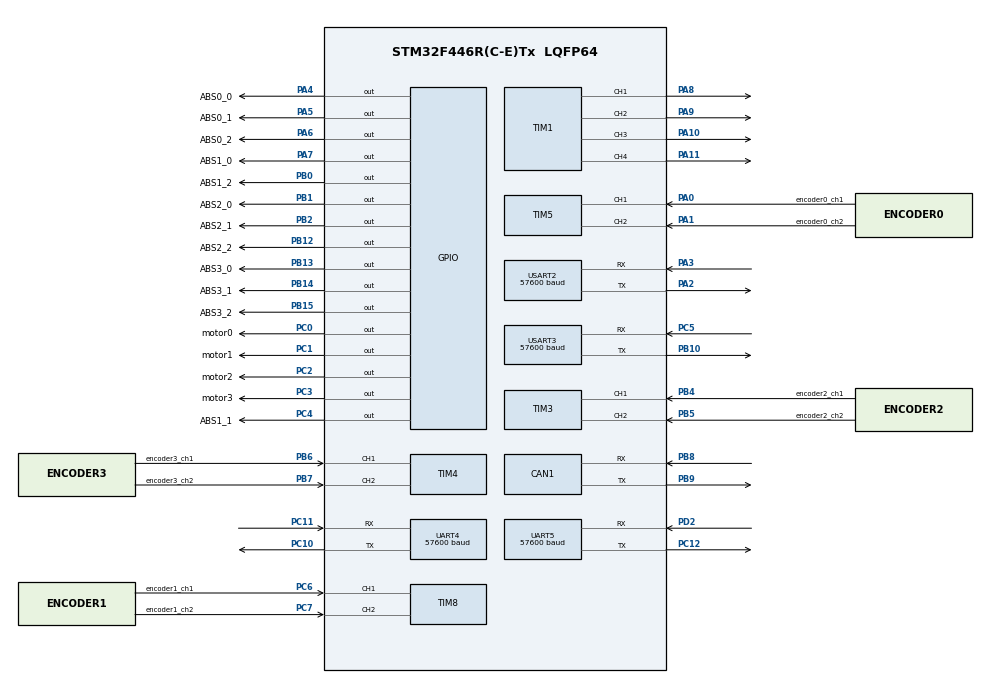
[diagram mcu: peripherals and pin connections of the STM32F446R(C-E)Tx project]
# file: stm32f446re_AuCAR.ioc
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CAN1.CalculateTimeQuantum=500.0
Dma.Request0=USART2_RX
Dma.Request1=USART2_TX
Dma.Request2=USART3_RX
Dma.Request3=USART3_TX
Dma.Request4=UART4_RX
Dma.Request5=UART4_TX
Dma.Request6=UART5_RX
Dma.Request7=UART5_TX
Dma.UART4_RX.4.Direction=DMA_PERIPH_TO_MEMORY
Dma.UART4_RX.4.FIFOMode=DMA_FIFOMODE_DISABLE
Dma.UART4_RX.4.Instance=DMA1_Stream2
Dma.UART4_RX.4.MemDataAlignment=DMA_MDATAALIGN_BYTE
Dma.UART4_RX.4.MemInc=DMA_MINC_ENABLE
Dma.UART4_RX.4.Mode=DMA_CIRCULAR
Dma.UART4_RX.4.PeriphDataAlignment=DMA_PDATAALIGN_BYTE
Dma.UART4_RX.4.PeriphInc=DMA_PINC_DISABLE
Dma.UART4_RX.4.Priority=DMA_PRIORITY_LOW
Dma.UART4_TX.5.Direction=DMA_MEMORY_TO_PERIPH
Dma.UART4_TX.5.FIFOMode=DMA_FIFOMODE_DISABLE
Dma.UART4_TX.5.Instance=DMA1_Stream4
Dma.UART4_TX.5.MemDataAlignment=DMA_MDATAALIGN_BYTE
Dma.UART4_TX.5.MemInc=DMA_MINC_ENABLE
Dma.UART4_TX.5.Mode=DMA_NORMAL
Dma.UART4_TX.5.PeriphDataAlignment=DMA_PDATAALIGN_BYTE
Dma.UART4_TX.5.PeriphInc=DMA_PINC_DISABLE
Dma.UART4_TX.5.Priority=DMA_PRIORITY_LOW
Dma.UART5_RX.6.Direction=DMA_PERIPH_TO_MEMORY
Dma.UART5_RX.6.FIFOMode=DMA_FIFOMODE_DISABLE
Dma.UART5_RX.6.Instance=DMA1_Stream0
Dma.UART5_RX.6.MemDataAlignment=DMA_MDATAALIGN_BYTE
Dma.UART5_RX.6.MemInc=DMA_MINC_ENABLE
Dma.UART5_RX.6.Mode=DMA_CIRCULAR
Dma.UART5_RX.6.PeriphDataAlignment=DMA_PDATAALIGN_BYTE
Dma.UART5_RX.6.PeriphInc=DMA_PINC_DISABLE
Dma.UART5_RX.6.Priority=DMA_PRIORITY_LOW
Dma.UART5_TX.7.Direction=DMA_MEMORY_TO_PERIPH
Dma.UART5_TX.7.FIFOMode=DMA_FIFOMODE_DISABLE
Dma.UART5_TX.7.Instance=DMA1_Stream7
Dma.UART5_TX.7.MemDataAlignment=DMA_MDATAALIGN_BYTE
Dma.UART5_TX.7.MemInc=DMA_MINC_ENABLE
Dma.UART5_TX.7.Mode=DMA_NORMAL
Dma.UART5_TX.7.PeriphDataAlignment=DMA_PDATAALIGN_BYTE
Dma.UART5_TX.7.PeriphInc=DMA_PINC_DISABLE
Dma.UART5_TX.7.Priority=DMA_PRIORITY_LOW
Dma.USART2_RX.0.Direction=DMA_PERIPH_TO_MEMORY
Dma.USART2_RX.0.FIFOMode=DMA_FIFOMODE_DISABLE
Dma.USART2_RX.0.Instance=DMA1_Stream5
Dma.USART2_RX.0.MemDataAlignment=DMA_MDATAALIGN_BYTE
Dma.USART2_RX.0.MemInc=DMA_MINC_ENABLE
Dma.USART2_RX.0.Mode=DMA_CIRCULAR
Dma.USART2_RX.0.PeriphDataAlignment=DMA_PDATAALIGN_BYTE
Dma.USART2_RX.0.PeriphInc=DMA_PINC_DISABLE
Dma.USART2_RX.0.Priority=DMA_PRIORITY_LOW
Dma.USART2_TX.1.Direction=DMA_MEMORY_TO_PERIPH
Dma.USART2_TX.1.FIFOMode=DMA_FIFOMODE_DISABLE
Dma.USART2_TX.1.Instance=DMA1_Stream6
Dma.USART2_TX.1.MemDataAlignment=DMA_MDATAALIGN_BYTE
Dma.USART2_TX.1.MemInc=DMA_MINC_ENABLE
Dma.USART2_TX.1.Mode=DMA_NORMAL
Dma.USART2_TX.1.PeriphDataAlignment=DMA_PDATAALIGN_BYTE
Dma.USART2_TX.1.PeriphInc=DMA_PINC_DISABLE
Dma.USART2_TX.1.Priority=DMA_PRIORITY_LOW
Dma.USART3_RX.2.Direction=DMA_PERIPH_TO_MEMORY
Dma.USART3_RX.2.FIFOMode=DMA_FIFOMODE_DISABLE
Dma.USART3_RX.2.Instance=DMA1_Stream1
Dma.USART3_RX.2.MemDataAlignment=DMA_MDATAALIGN_BYTE
Dma.USART3_RX.2.MemInc=DMA_MINC_ENABLE
Dma.USART3_RX.2.Mode=DMA_CIRCULAR
Dma.USART3_RX.2.PeriphDataAlignment=DMA_PDATAALIGN_BYTE
Dma.USART3_RX.2.PeriphInc=DMA_PINC_DISABLE
Dma.USART3_RX.2.Priority=DMA_PRIORITY_LOW
Dma.USART3_TX.3.Direction=DMA_MEMORY_TO_PERIPH
Dma.USART3_TX.3.FIFOMode=DMA_FIFOMODE_DISABLE
Dma.USART3_TX.3.Instance=DMA1_Stream3
Dma.USART3_TX.3.MemDataAlignment=DMA_MDATAALIGN_BYTE
Dma.USART3_TX.3.MemInc=DMA_MINC_ENABLE
Dma.USART3_TX.3.Mode=DMA_NORMAL
Dma.USART3_TX.3.PeriphDataAlignment=DMA_PDATAALIGN_BYTE
Dma.USART3_TX.3.PeriphInc=DMA_PINC_DISABLE
Dma.USART3_TX.3.Priority=DMA_PRIORITY_LOW
Mcu.Family=STM32F4
Mcu.Name=STM32F446R(C-E)Tx
Mcu.Package=LQFP64
NVIC.CAN1_RX0_IRQn=true\:0\:0\:false\:false\:true\:true\:true
NVIC.CAN1_RX1_IRQn=true\:0\:0\:false\:false\:true\:true\:true
NVIC.CAN1_SCE_IRQn=true\:0\:0\:false\:false\:true\:true\:true
NVIC.CAN1_TX_IRQn=true\:0\:0\:false\:false\:true\:true\:true
NVIC.DMA1_Stream0_IRQn=true\:0\:0\:false\:false\:true\:false\:true
NVIC.DMA1_Stream1_IRQn=true\:0\:0\:false\:false\:true\:false\:true
NVIC.DMA1_Stream2_IRQn=true\:0\:0\:false\:false\:true\:false\:true
NVIC.DMA1_Stream3_IRQn=true\:0\:0\:false\:false\:true\:false\:true
NVIC.DMA1_Stream4_IRQn=true\:0\:0\:false\:false\:true\:false\:true
NVIC.DMA1_Stream5_IRQn=true\:0\:0\:false\:false\:true\:false\:true
NVIC.DMA1_Stream6_IRQn=true\:0\:0\:false\:false\:true\:false\:true
NVIC.DMA1_Stream7_IRQn=true\:0\:0\:false\:false\:true\:false\:true
NVIC.PriorityGroup=NVIC_PRIORITYGROUP_4
NVIC.RCC_IRQn=true\:0\:0\:false\:false\:true\:true\:false
NVIC.TIM3_IRQn=true\:0\:0\:false\:false\:true\:true\:true
NVIC.TIM4_IRQn=true\:0\:0\:false\:false\:true\:true\:true
NVIC.UART4_IRQn=true\:0\:0\:false\:false\:true\:true\:true
NVIC.UART5_IRQn=true\:0\:0\:false\:false\:true\:true\:true
NVIC.USART2_IRQn=true\:0\:0\:false\:false\:true\:true\:true
NVIC.USART3_IRQn=true\:0\:0\:false\:false\:true\:true\:true
PA0-WKUP.GPIO_Label=encoder0_ch1
PA0-WKUP.Signal=S_TIM5_CH1
PA1.GPIO_Label=encoder0_ch2
PA1.Signal=S_TIM5_CH2
PA10.Signal=S_TIM1_CH3
PA11.Signal=S_TIM1_CH4
PA13.Mode=Serial_Wire
PA13.Signal=SYS_JTMS-SWDIO
PA14.Mode=Serial_Wire
PA14.Signal=SYS_JTCK-SWCLK
PA2.Mode=Asynchronous
PA2.Signal=USART2_TX
PA3.Mode=Asynchronous
PA3.Signal=USART2_RX
PA4.GPIO_Label=ABS0_0
PA4.Signal=GPIO_Output
PA5.GPIO_Label=ABS0_1
PA5.Signal=GPIO_Output
PA6.GPIO_Label=ABS0_2
PA6.Signal=GPIO_Output
PA7.GPIO_Label=ABS1_0
PA7.Signal=GPIO_Output
PA8.Signal=S_TIM1_CH1
PA9.Signal=S_TIM1_CH2
PB0.GPIO_Label=ABS1_2
PB0.Signal=GPIO_Output
PB1.GPIO_Label=ABS2_0
PB1.Signal=GPIO_Output
PB10.Mode=Asynchronous
PB10.Signal=USART3_TX
PB12.GPIO_Label=ABS2_2
PB12.Signal=GPIO_Output
PB13.GPIO_Label=ABS3_0
PB13.Signal=GPIO_Output
PB14.GPIO_Label=ABS3_1
PB14.Signal=GPIO_Output
PB15.GPIO_Label=ABS3_2
PB15.Signal=GPIO_Output
PB2.GPIO_Label=ABS2_1
PB2.Signal=GPIO_Output
PB4.GPIO_Label=encoder2_ch1
PB4.Signal=S_TIM3_CH1
PB5.GPIO_Label=encoder2_ch2
PB5.Signal=S_TIM3_CH2
PB6.GPIO_Label=encoder3_ch1
PB6.Signal=S_TIM4_CH1
PB7.GPIO_Label=encoder3_ch2
PB7.Signal=S_TIM4_CH2
PB8.Mode=Master
PB8.Signal=CAN1_RX
PB9.Mode=Master
PB9.Signal=CAN1_TX
PC0.GPIO_Label=motor0
PC0.Signal=GPIO_Output
PC1.GPIO_Label=motor1
PC1.Signal=GPIO_Output
PC10.Mode=Asynchronous
PC10.Signal=UART4_TX
PC11.Mode=Asynchronous
PC11.Signal=UART4_RX
PC12.Mode=Asynchronous
PC12.Signal=UART5_TX
PC2.GPIO_Label=motor2
PC2.Signal=GPIO_Output
PC3.GPIO_Label=motor3
PC3.Signal=GPIO_Output
PC4.GPIO_Label=ABS1_1
PC4.Signal=GPIO_Output
PC5.Mode=Asynchronous
PC5.Signal=USART3_RX
PC6.GPIO_Label=encoder1_ch1
PC6.Signal=S_TIM8_CH1
PC7.GPIO_Label=encoder1_ch2
PC7.Signal=S_TIM8_CH2
PD2.Mode=Asynchronous
PD2.Signal=UART5_RX
PH0-OSC_IN.Mode=HSE-External-Oscillator
PH0-OSC_IN.Signal=RCC_OSC_IN
PH1-OSC_OUT.Mode=HSE-External-Oscillator
PH1-OSC_OUT.Signal=RCC_OSC_OUT
ProjectManager.HeapSize=0x200
ProjectManager.StackSize=0x400
ProjectManager.TargetToolchain=STM32CubeIDE
RCC.AHBFreq_Value=128000000
RCC.APB1CLKDivider=RCC_HCLK_DIV4
RCC.APB1Freq_Value=32000000
RCC.APB1TimFreq_Value=64000000
RCC.APB2CLKDivider=RCC_HCLK_DIV4
RCC.APB2Freq_Value=32000000
RCC.APB2TimFreq_Value=64000000
RCC.CortexFreq_Value=128000000
RCC.HCLKFreq_Value=128000000
RCC.HSE_VALUE=16000000
RCC.PLLM=8
RCC.PLLN=128
RCC.SYSCLKFreq_VALUE=128000000
RCC.SYSCLKSource=RCC_SYSCLKSOURCE_PLLCLK
RCC.USBFreq_Value=128000000
RCC.VCOOutputFreq_Value=256000000
SH.S_TIM1_CH1.0=TIM1_CH1,PWM Generation1 CH1
SH.S_TIM1_CH2.0=TIM1_CH2,PWM Generation2 CH2
SH.S_TIM1_CH3.0=TIM1_CH3,PWM Generation3 CH3
SH.S_TIM1_CH4.0=TIM1_CH4,PWM Generation4 CH4
SH.S_TIM3_CH1.0=TIM3_CH1,Encoder_Interface
SH.S_TIM3_CH2.0=TIM3_CH2,Encoder_Interface
SH.S_TIM4_CH1.0=TIM4_CH1,Encoder_Interface
SH.S_TIM4_CH2.0=TIM4_CH2,Encoder_Interface
SH.S_TIM5_CH1.0=TIM5_CH1,Encoder_Interface
SH.S_TIM5_CH2.0=TIM5_CH2,Encoder_Interface
SH.S_TIM8_CH1.0=TIM8_CH1,Encoder_Interface
SH.S_TIM8_CH2.0=TIM8_CH2,Encoder_Interface
TIM1.Channel-PWM\ Generation1\ CH1=TIM_CHANNEL_1
TIM1.Channel-PWM\ Generation2\ CH2=TIM_CHANNEL_2
TIM1.Channel-PWM\ Generation3\ CH3=TIM_CHANNEL_3
TIM1.Channel-PWM\ Generation4\ CH4=TIM_CHANNEL_4
TIM2.Period=0xFFFFFFFF
TIM2.Prescaler=64000-1
UART4.BaudRate=57600
UART4.VirtualMode=Asynchronous
UART5.BaudRate=57600
UART5.VirtualMode=Asynchronous
USART2.BaudRate=57600
USART2.VirtualMode=VM_ASYNC
USART3.BaudRate=57600
USART3.VirtualMode=VM_ASYNC
VP_TIM2_VS_ClockSourceINT.Mode=Internal
board=custom

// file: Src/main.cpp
/* USER CODE BEGIN Header */
/**
  ******************************************************************************
  * @file           : main.c
  * @brief          : Main program body
  ******************************************************************************
  * @attention
  *
  * <h2><center>&copy; Copyright (c) 2019 STMicroelectronics.
  * All rights reserved.</center></h2>
  *
  * This software component is licensed by ST under BSD 3-Clause license,
  * the "License"; You may not use this file except in compliance with the
  * License. You may obtain a copy of the License at:
  *                        opensource.org/licenses/BSD-3-Clause
  *
  ******************************************************************************
  */
/* USER CODE END Header */

#include "main.h"
#include "can.h"
#include "dma.h"
#include "tim.h"
#include "usart.h"
#include "gpio.h"

#include <ros/time.h>
#include <ros.h>
#include <std_msgs/String.h>
#include <std_msgs/Int16.h>
#include <sensor_msgs/Imu.h>
#include <sensor_msgs/BatteryState.h>
#include <std_msgs/Header.h>
#include <aucar_msgs/AuCAR.h>
#include <aucar_msgs/SwerveDrive.h>

/* USER CODE BEGIN PV */
ros::NodeHandle nh;

std_msgs::String str_msg;
std_msgs::String str_device;

aucar_msgs::AuCAR aucar_msg;
aucar_msgs::SwerveDrive swerve_drive_msg;

ros::Publisher pub_chat("chatter", &str_msg);
ros::Publisher pub_device("dev_info", &str_device);
ros::Publisher pub_aucar("aucar", &aucar_msg);

char hello[] = "Hello world!";
char device_info[] = "STM32F446RE\r\nACSL_interface_board\r\nDesigned by YeongJunKim\r\ncolson@korea.ac.kr";

void HAL_UART_TxCpltCallback(UART_HandleTypeDef *huart){
  nh.getHardware()->flush();
}

void HAL_UART_RxCpltCallback(UART_HandleTypeDef *huart){
   nh.getHardware()->reset_rbuf();
}

/* USER CODE END PV */

void SystemClock_Config(void);

int main(void)
{

  /* MCU Configuration--------------------------------------------------------*/

  /* Reset of all peripherals, Initializes the Flash interface and the Systick. */
  HAL_Init();

  /* Configure the system clock */
  SystemClock_Config();

  /* Initialize all configured peripherals */
  MX_GPIO_Init();
  MX_DMA_Init();
  MX_TIM1_Init();
  MX_TIM2_Init();
  MX_TIM3_Init();
  MX_TIM4_Init();
  MX_TIM5_Init();
  MX_TIM8_Init();
  MX_CAN1_Init();
  MX_UART4_Init();
  MX_USART2_UART_Init();
  MX_USART3_UART_Init();
  MX_UART5_Init();
  /* USER CODE BEGIN 2 */

  nh.initNode();
  nh.advertise(pub_chat);
  nh.advertise(pub_device);
  nh.advertise(pub_aucar);
  /* USER CODE END 2 */

  /* Infinite loop */
  while (1)
  {
	  str_msg.data = hello;
	  str_device.data = device_info;
	  hello[11]++;
	  if(hello[11] > 127)
		  hello[11] = 0;

	  pub_chat.publish(&str_msg);
	  pub_device.publish(&str_device);

	  nh.spinOnce();

	  HAL_Delay(50);
  }
}

void SystemClock_Config(void)
{
  RCC_OscInitTypeDef RCC_OscInitStruct = {0};
  RCC_ClkInitTypeDef RCC_ClkInitStruct = {0};

  /** Configure the main internal regulator output voltage
  */
  __HAL_RCC_PWR_CLK_ENABLE();
  __HAL_PWR_VOLTAGESCALING_CONFIG(PWR_REGULATOR_VOLTAGE_SCALE3);
  /** Initializes the CPU, AHB and APB busses clocks
  */
  RCC_OscInitStruct.OscillatorType = RCC_OSCILLATORTYPE_HSI;
  RCC_OscInitStruct.HSIState = RCC_HSI_ON;
  RCC_OscInitStruct.HSICalibrationValue = RCC_HSICALIBRATION_DEFAULT;
  RCC_OscInitStruct.PLL.PLLState = RCC_PLL_ON;
  RCC_OscInitStruct.PLL.PLLSource = RCC_PLLSOURCE_HSI;
  RCC_OscInitStruct.PLL.PLLM = 8;
  RCC_OscInitStruct.PLL.PLLN = 64;
  RCC_OscInitStruct.PLL.PLLP = RCC_PLLP_DIV2;
  RCC_OscInitStruct.PLL.PLLQ = 2;
  RCC_OscInitStruct.PLL.PLLR = 2;
  if (HAL_RCC_OscConfig(&RCC_OscInitStruct) != HAL_OK)
  {
    Error_Handler();
  }
  /** Initializes the CPU, AHB and APB busses clocks
  */
  RCC_ClkInitStruct.ClockType = RCC_CLOCKTYPE_HCLK|RCC_CLOCKTYPE_SYSCLK
                              |RCC_CLOCKTYPE_PCLK1|RCC_CLOCKTYPE_PCLK2;
  RCC_ClkInitStruct.SYSCLKSource = RCC_SYSCLKSOURCE_PLLCLK;
  RCC_ClkInitStruct.AHBCLKDivider = RCC_SYSCLK_DIV1;
  RCC_ClkInitStruct.APB1CLKDivider = RCC_HCLK_DIV2;
  RCC_ClkInitStruct.APB2CLKDivider = RCC_HCLK_DIV1;

  if (HAL_RCC_ClockConfig(&RCC_ClkInitStruct, FLASH_LATENCY_2) != HAL_OK)
  {
    Error_Handler();
  }
}

void Error_Handler(void)
{
}

/************************ (C) COPYRIGHT STMicroelectronics *****END OF FILE****/
